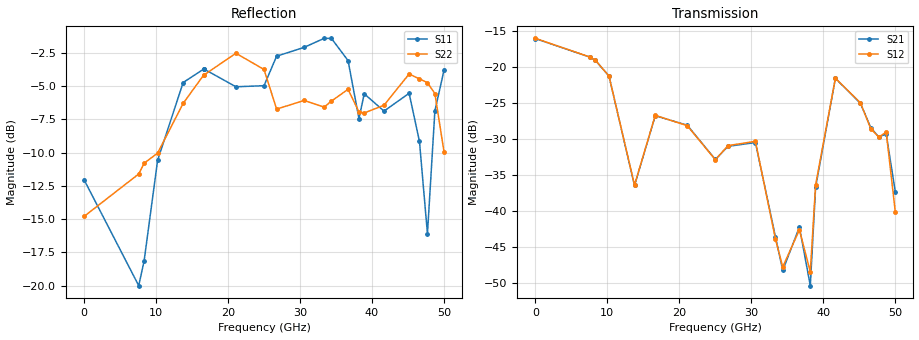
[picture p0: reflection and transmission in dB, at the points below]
!Keysight Technologies,N5245B,MY58422270,A.16.20.02
!Date: Thursday, March 05, 2026 01:14:31
!Correction: S11(C  2-Port  )
!S21(C  2-Port  )
!S12(C  2-Port  )
!S22(C  2-Port  )
!S2P File: Measurements: S11, S21, S12, S22:
# Hz S  dB  R 50
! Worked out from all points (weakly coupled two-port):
!   3201 points, 10 MHz to 50 GHz, reference 50 ohm
!   highest |S21| = -16.00 dB at 10 MHz (marker M1); lowest = -50.4 dB at 38.19 GHz (marker M2)
!   lowest |S11| = -20.0 dB at 7.602 GHz (marker M3), VSWR 1.22, Z = 41 - j0.984 ohm
!   |S11| at or under -10 dB: start of sweep to 10.43 GHz; 46.73 GHz to 48.25 GHz (1.521 GHz wide, 3.2 % of centre)
!   |S22| runs from -18.6 to -2.5 dB; largest |S21 - S12| = 0.0047
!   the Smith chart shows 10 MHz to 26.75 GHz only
!   S11 on the Smith chart (normalised r, x): 10 MHz: 1.67, -0.02; 10.23 GHz: 0.55, +0.11; 13.77 GHz: 1.08, +1.48; 16.63 GHz: 1.33, -1.96; 21.1 GHz: 0.33, -0.37; 26.75 GHz: 0.17, +0.33
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1e7  -12.03 -1.4  -16.00 2.6  -15.97 4.3  -14.79 40.4
7.602231e9  -20.00 -173.2  -18.59 39.9  -18.58 40.0  -11.60 -163.3
8.352081e9  -18.13 -162.6  -19.05 6.4  -19.03 6.4  -10.79 179.9
1.022671e10  -10.57 162.9  -21.21 -76.5  -21.21 -76.6  -10.03 122.0
1.377287e10  -4.72 51.5  -36.46 -164.6  -36.41 -165.4  -6.29 -52.4
1.663168e10  -3.71 -40.3  -26.82 160.8  -26.78 160.8  -4.15 -143.5
1.667854e10  -3.71 -41.7  -26.75 159.1  -26.70 159.0  -4.15 -144.4
2.109953e10  -5.04 -135.4  -28.07 21.3  -28.13 21.7  -2.52 137.7
2.5005e10  -4.96 174.6  -32.84 -66.9  -32.88 -67.9  -3.74 70.5
2.675465e10  -2.74 142.7  -31.01 -104.0  -30.91 -103.6  -6.72 38.9
3.056639e10  -2.08 80.0  -30.48 123.9  -30.31 123.9  -6.07 -51.7
3.334708e10  -1.40 35.7  -43.60 -1.6  -43.91 3.9  -6.57 -133.1
3.43625e10  -1.40 18.0  -48.29 -105.9  -47.80 -108.5  -6.12 -155.7
3.667454e10  -3.07 -30.8  -42.26 102.3  -42.64 107.0  -5.23 158.8
3.818986e10  -7.43 -22.2  -50.42 80.9  -48.50 73.4  -6.93 133.9
3.892409e10  -5.57 -29.8  -36.74 99.6  -36.39 101.7  -7.01 136.9
4.167354e10  -6.87 -55.2  -21.53 -56.8  -21.53 -56.6  -6.43 110.2
4.515722e10  -5.53 -102.4  -25.03 82.9  -24.96 82.9  -4.08 73.7
4.659443e10  -9.15 -153.4  -28.42 31.2  -28.57 31.3  -4.45 53.9
4.770358e10  -16.10 71.8  -29.71 -15.4  -29.72 -14.2  -4.73 41.8
4.873463e10  -6.86 -25.7  -29.29 -88.0  -29.03 -89.6  -5.55 21.0
5e10  -3.81 -72.7  -37.39 -124.1  -40.19 -130.7  -9.91 8.8
